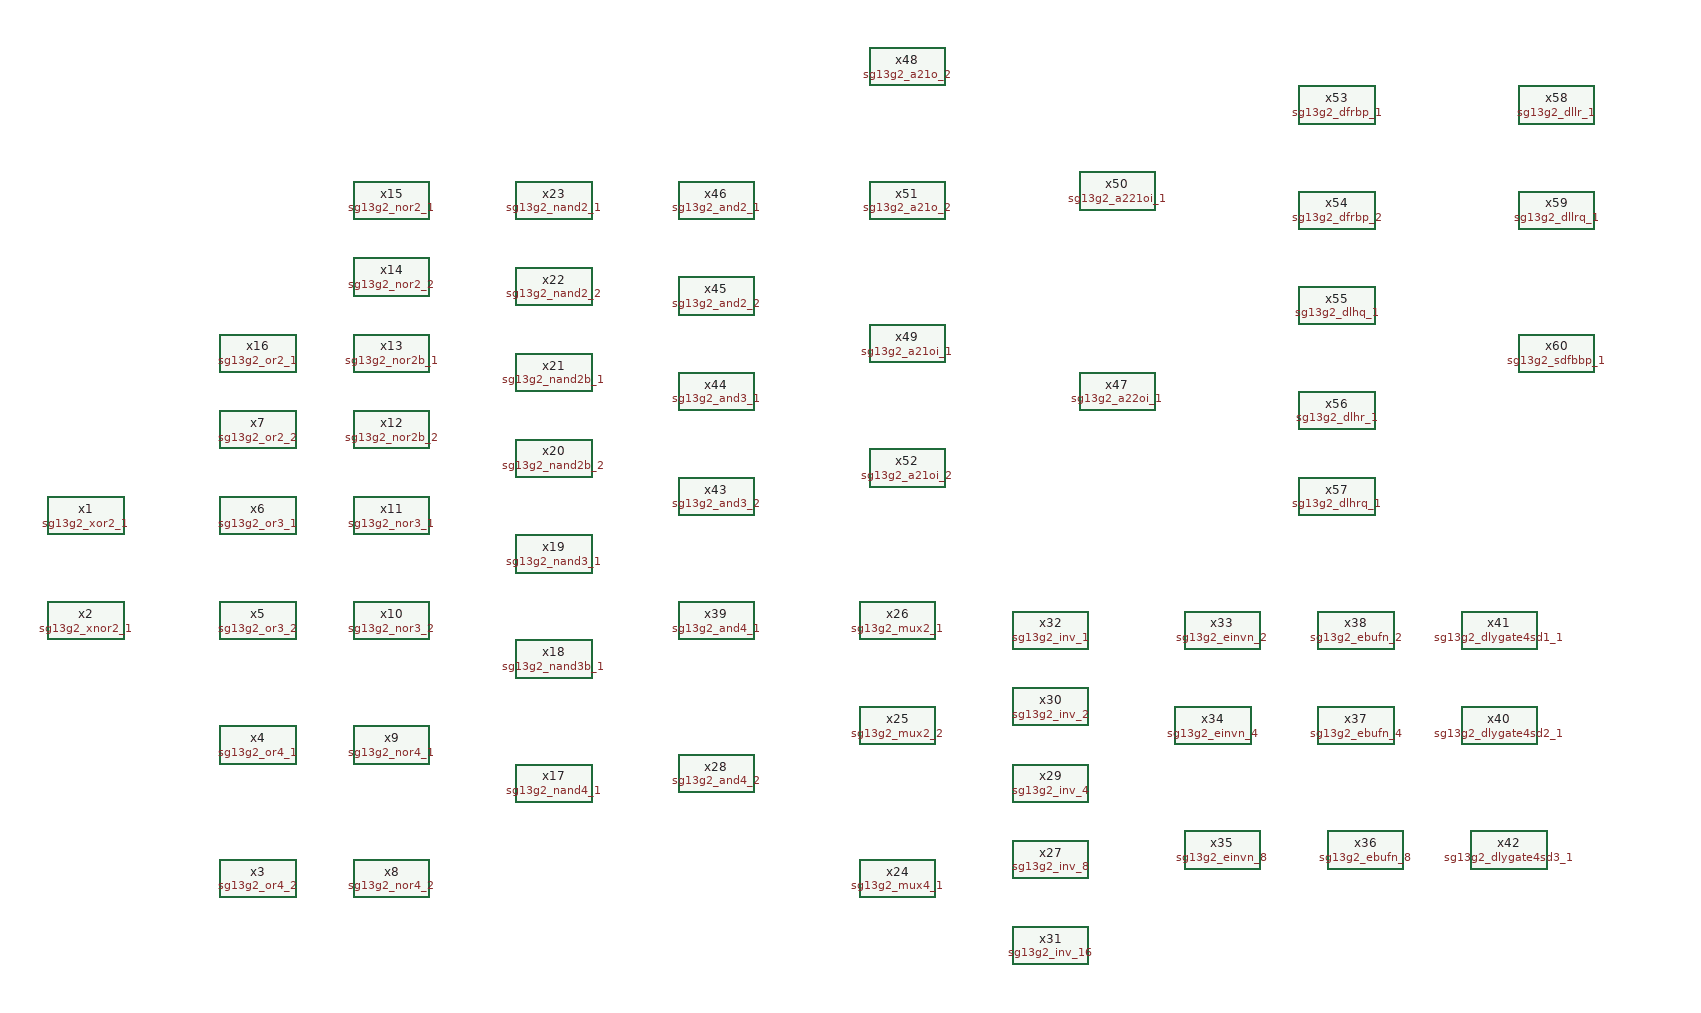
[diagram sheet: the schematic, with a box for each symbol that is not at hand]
v {xschem version=3.4.5 file_version=1.2
}
G {}
K {}
V {}
S {}
E {}
C {devices/title.sym} -90 0 0 0 {name=l1 author="IHP PDK Authors"}
C {sg13g2_stdcells/sg13g2_xor2_1.sym} -300 -540 0 0 {name=x1 VDD=VDD VSS=VSS prefix=sg13g2_ }
C {sg13g2_stdcells/sg13g2_xnor2_1.sym} -300 -430 0 0 {name=x2 VDD=VDD VSS=VSS prefix=sg13g2_ }
C {sg13g2_stdcells/sg13g2_or4_2.sym} -120 -160 0 0 {name=x3 VDD=VDD VSS=VSS prefix=sg13g2_ }
C {sg13g2_stdcells/sg13g2_or4_1.sym} -120 -300 0 0 {name=x4 VDD=VDD VSS=VSS prefix=sg13g2_ }
C {sg13g2_stdcells/sg13g2_or3_2.sym} -120 -430 0 0 {name=x5 VDD=VDD VSS=VSS prefix=sg13g2_ }
C {sg13g2_stdcells/sg13g2_or3_1.sym} -120 -540 0 0 {name=x6 VDD=VDD VSS=VSS prefix=sg13g2_ }
C {sg13g2_stdcells/sg13g2_or2_2.sym} -120 -630 0 0 {name=x7 VDD=VDD VSS=VSS prefix=sg13g2_ }
C {sg13g2_stdcells/sg13g2_nor4_2.sym} 20 -160 0 0 {name=x8 VDD=VDD VSS=VSS prefix=sg13g2_ }
C {sg13g2_stdcells/sg13g2_nor4_1.sym} 20 -300 0 0 {name=x9 VDD=VDD VSS=VSS prefix=sg13g2_ }
C {sg13g2_stdcells/sg13g2_nor3_2.sym} 20 -430 0 0 {name=x10 VDD=VDD VSS=VSS prefix=sg13g2_ }
C {sg13g2_stdcells/sg13g2_nor3_1.sym} 20 -540 0 0 {name=x11 VDD=VDD VSS=VSS prefix=sg13g2_ }
C {sg13g2_stdcells/sg13g2_nor2b_2.sym} 20 -630 0 0 {name=x12 VDD=VDD VSS=VSS prefix=sg13g2_ }
C {sg13g2_stdcells/sg13g2_nor2b_1.sym} 20 -710 0 0 {name=x13 VDD=VDD VSS=VSS prefix=sg13g2_ }
C {sg13g2_stdcells/sg13g2_nor2_2.sym} 20 -790 0 0 {name=x14 VDD=VDD VSS=VSS prefix=sg13g2_ }
C {sg13g2_stdcells/sg13g2_nor2_1.sym} 20 -870 0 0 {name=x15 VDD=VDD VSS=VSS prefix=sg13g2_ }
C {sg13g2_stdcells/sg13g2_or2_1.sym} -120 -710 0 0 {name=x16 VDD=VDD VSS=VSS prefix=sg13g2_ }
C {sg13g2_stdcells/sg13g2_nand4_1.sym} 190 -260 0 0 {name=x17 VDD=VDD VSS=VSS prefix=sg13g2_ }
C {sg13g2_stdcells/sg13g2_nand3b_1.sym} 190 -390 0 0 {name=x18 VDD=VDD VSS=VSS prefix=sg13g2_ }
C {sg13g2_stdcells/sg13g2_nand3_1.sym} 190 -500 0 0 {name=x19 VDD=VDD VSS=VSS prefix=sg13g2_ }
C {sg13g2_stdcells/sg13g2_nand2b_2.sym} 190 -600 0 0 {name=x20 VDD=VDD VSS=VSS prefix=sg13g2_ }
C {sg13g2_stdcells/sg13g2_nand2b_1.sym} 190 -690 0 0 {name=x21 VDD=VDD VSS=VSS prefix=sg13g2_ }
C {sg13g2_stdcells/sg13g2_nand2_2.sym} 190 -780 0 0 {name=x22 VDD=VDD VSS=VSS prefix=sg13g2_ }
C {sg13g2_stdcells/sg13g2_nand2_1.sym} 190 -870 0 0 {name=x23 VDD=VDD VSS=VSS prefix=sg13g2_ }
C {sg13g2_stdcells/sg13g2_mux4_1.sym} 550 -160 0 0 {name=x24 VDD=VDD VSS=VSS prefix=sg13g2_ }
C {sg13g2_stdcells/sg13g2_mux2_2.sym} 550 -320 0 0 {name=x25 VDD=VDD VSS=VSS prefix=sg13g2_ }
C {sg13g2_stdcells/sg13g2_mux2_1.sym} 550 -430 0 0 {name=x26 VDD=VDD VSS=VSS prefix=sg13g2_ }
C {sg13g2_stdcells/sg13g2_inv_8.sym} 710 -180 0 0 {name=x27 VDD=VDD VSS=VSS prefix=sg13g2_ }
C {sg13g2_stdcells/sg13g2_inv_4.sym} 710 -260 0 0 {name=x29 VDD=VDD VSS=VSS prefix=sg13g2_ }
C {sg13g2_stdcells/sg13g2_inv_2.sym} 710 -340 0 0 {name=x30 VDD=VDD VSS=VSS prefix=sg13g2_ }
C {sg13g2_stdcells/sg13g2_inv_16.sym} 710 -90 0 0 {name=x31 VDD=VDD VSS=VSS prefix=sg13g2_ }
C {sg13g2_stdcells/sg13g2_inv_1.sym} 710 -420 0 0 {name=x32 VDD=VDD VSS=VSS prefix=sg13g2_ }
C {sg13g2_stdcells/sg13g2_einvn_2.sym} 890 -420 0 0 {name=x33 VDD=VDD VSS=VSS prefix=sg13g2_ }
C {sg13g2_stdcells/sg13g2_einvn_4.sym} 880 -320 0 0 {name=x34 VDD=VDD VSS=VSS prefix=sg13g2_ }
C {sg13g2_stdcells/sg13g2_einvn_8.sym} 890 -190 0 0 {name=x35 VDD=VDD VSS=VSS prefix=sg13g2_ }
C {sg13g2_stdcells/sg13g2_ebufn_8.sym} 1040 -190 0 0 {name=x36 VDD=VDD VSS=VSS prefix=sg13g2_ }
C {sg13g2_stdcells/sg13g2_ebufn_4.sym} 1030 -320 0 0 {name=x37 VDD=VDD VSS=VSS prefix=sg13g2_ }
C {sg13g2_stdcells/sg13g2_ebufn_2.sym} 1030 -420 0 0 {name=x38 VDD=VDD VSS=VSS prefix=sg13g2_ }
C {sg13g2_stdcells/sg13g2_dlygate4sd2_1.sym} 1180 -320 0 0 {name=x40 VDD=VDD VSS=VSS prefix=sg13g2_ }
C {sg13g2_stdcells/sg13g2_dlygate4sd1_1.sym} 1180 -420 0 0 {name=x41 VDD=VDD VSS=VSS prefix=sg13g2_ }
C {sg13g2_stdcells/sg13g2_dlygate4sd3_1.sym} 1190 -190 0 0 {name=x42 VDD=VDD VSS=VSS prefix=sg13g2_ }
C {sg13g2_stdcells/sg13g2_and4_2.sym} 360 -270 0 0 {name=x28 VDD=VDD VSS=VSS prefix=sg13g2_ }
C {sg13g2_stdcells/sg13g2_and4_1.sym} 360 -430 0 0 {name=x39 VDD=VDD VSS=VSS prefix=sg13g2_ }
C {sg13g2_stdcells/sg13g2_and3_2.sym} 360 -560 0 0 {name=x43 VDD=VDD VSS=VSS prefix=sg13g2_ }
C {sg13g2_stdcells/sg13g2_and3_1.sym} 360 -670 0 0 {name=x44 VDD=VDD VSS=VSS prefix=sg13g2_ }
C {sg13g2_stdcells/sg13g2_and2_2.sym} 360 -770 0 0 {name=x45 VDD=VDD VSS=VSS prefix=sg13g2_ }
C {sg13g2_stdcells/sg13g2_and2_1.sym} 360 -870 0 0 {name=x46 VDD=VDD VSS=VSS prefix=sg13g2_ }
C {sg13g2_stdcells/sg13g2_a22oi_1.sym} 780 -670 0 0 {name=x47 VDD=VDD VSS=VSS prefix=sg13g2_ }
C {sg13g2_stdcells/sg13g2_a21o_2.sym} 560 -1010 0 0 {name=x48 VDD=VDD VSS=VSS prefix=sg13g2_ }
C {sg13g2_stdcells/sg13g2_a21oi_1.sym} 560 -720 0 0 {name=x49 VDD=VDD VSS=VSS prefix=sg13g2_ }
C {sg13g2_stdcells/sg13g2_a221oi_1.sym} 780 -880 0 0 {name=x50 VDD=VDD VSS=VSS prefix=sg13g2_ }
C {sg13g2_stdcells/sg13g2_a21o_2.sym} 560 -870 0 0 {name=x51 VDD=VDD VSS=VSS prefix=sg13g2_ }
C {sg13g2_stdcells/sg13g2_a21oi_2.sym} 560 -590 0 0 {name=x52 VDD=VDD VSS=VSS prefix=sg13g2_ }
C {sg13g2_stdcells/sg13g2_dfrbp_1.sym} 1010 -970 0 0 {name=x53 VDD=VDD VSS=VSS prefix=sg13g2_ }
C {sg13g2_stdcells/sg13g2_dfrbp_2.sym} 1010 -860 0 0 {name=x54 VDD=VDD VSS=VSS prefix=sg13g2_ }
C {sg13g2_stdcells/sg13g2_dlhq_1.sym} 1010 -760 0 0 {name=x55 VDD=VDD VSS=VSS prefix=sg13g2_ }
C {sg13g2_stdcells/sg13g2_dlhr_1.sym} 1010 -650 0 0 {name=x56 VDD=VDD VSS=VSS prefix=sg13g2_ }
C {sg13g2_stdcells/sg13g2_dlhrq_1.sym} 1010 -560 0 0 {name=x57 VDD=VDD VSS=VSS prefix=sg13g2_ }
C {sg13g2_stdcells/sg13g2_dllr_1.sym} 1240 -970 0 0 {name=x58 VDD=VDD VSS=VSS prefix=sg13g2_ }
C {sg13g2_stdcells/sg13g2_dllrq_1.sym} 1240 -860 0 0 {name=x59 VDD=VDD VSS=VSS prefix=sg13g2_ }
C {sg13g2_stdcells/sg13g2_sdfbbp_1.sym} 1240 -710 0 0 {name=x60 VDD=VDD VSS=VSS prefix=sg13g2_ }
